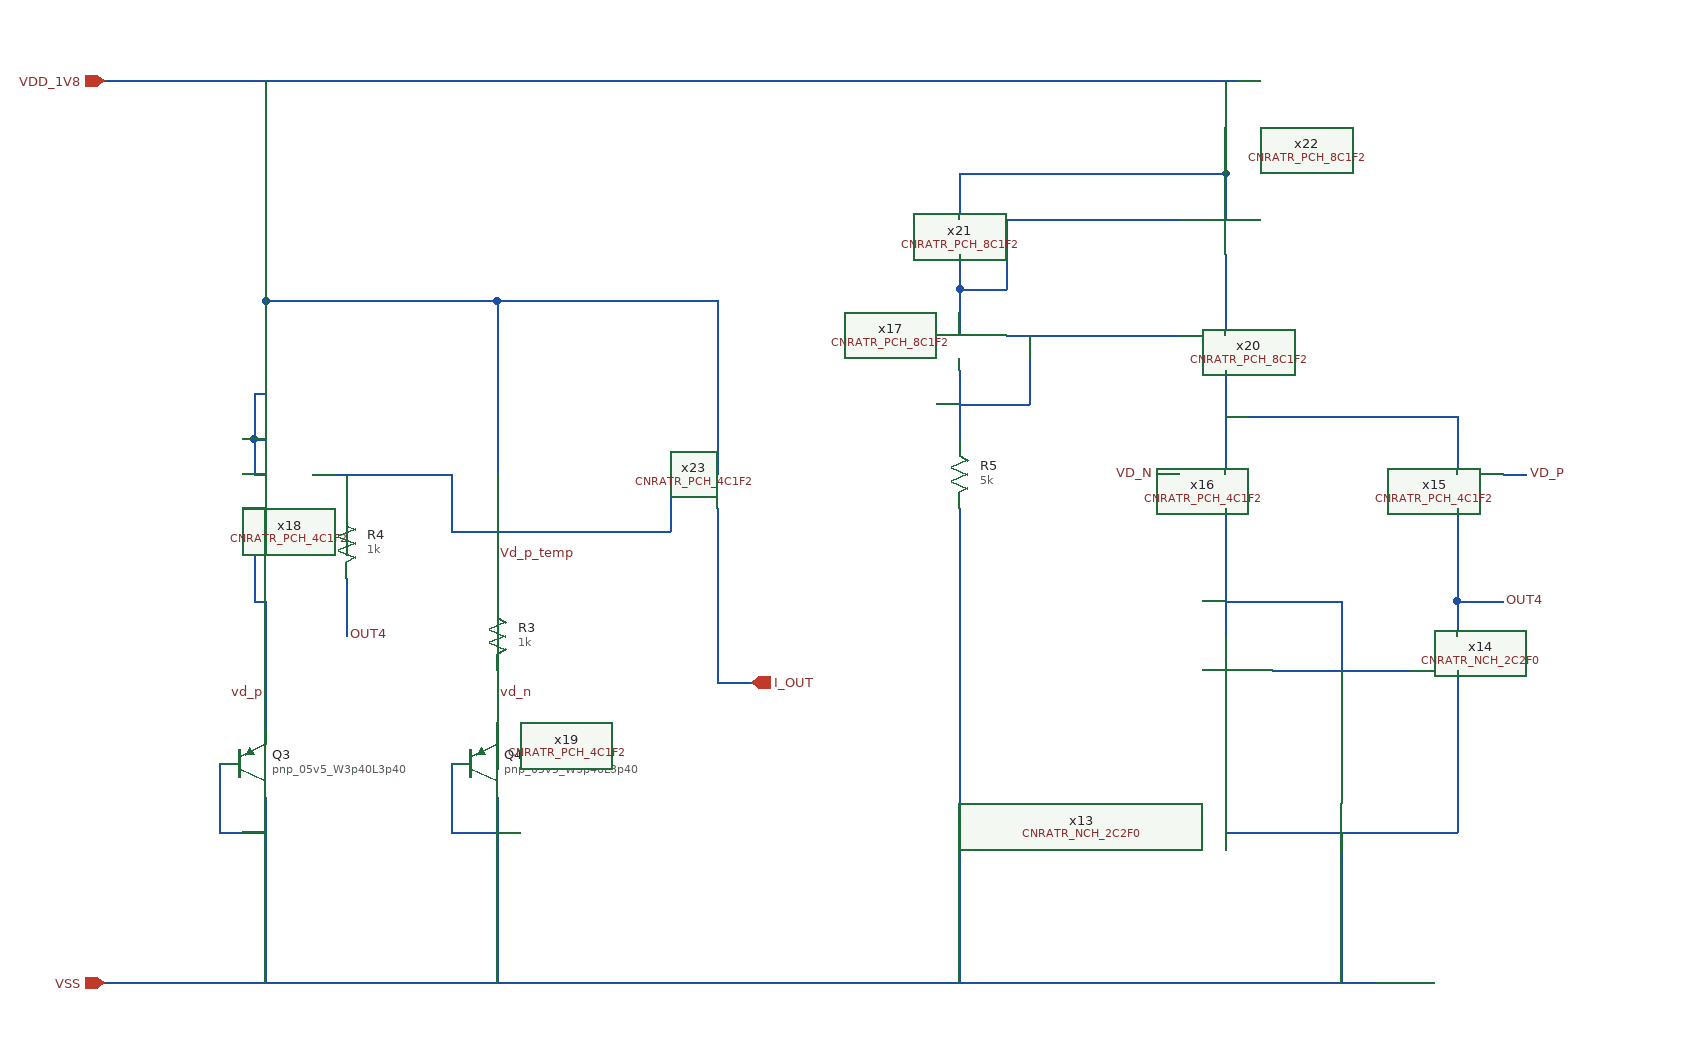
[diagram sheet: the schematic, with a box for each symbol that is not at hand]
v {xschem version=3.4.4 file_version=1.2
}
G {}
K {}
V {}
S {}
E {}
N -40 250 -40 310 {
lab=VSS}
N 160 250 160 310 {
lab=VSS}
N 160 310 180 310 {
lab=VSS}
N 200 280 200 330 {
lab=VSS}
N 180 310 200 310 {
lab=VSS}
N 0 290 0 330 {
lab=VSS}
N -40 310 0 310 {
lab=VSS}
N 0 280 0 290 {
lab=VSS}
N 200 -30 200 0 {
lab=VDD_1V8}
N 200 170 200 220 {
lab=vd_n}
N 200 30 200 110 {
lab=Vd_p_temp}
N 40 0 160 0 {
lab=#net1}
N 70 0 70 30 {
lab=#net1}
N 0 170 0 230 {
lab=vd_p}
N 0 110 0 170 {
lab=vd_p}
N 70 90 70 140 {
lab=OUT4}
N 390 30 390 160 {
lab=I_OUT}
N 390 -30 390 0 {
lab=VDD_1V8}
N 160 0 160 50 {
lab=#net1}
N 160 50 350 50 {
lab=#net1}
N 350 0 350 50 {
lab=#net1}
N 0 -130 0 -100 {
lab=VDD_1V8}
N 0 -150 0 -130 {
lab=VDD_1V8}
N 0 -150 200 -150 {
lab=VDD_1V8}
N 200 -150 200 -130 {
lab=VDD_1V8}
N 200 -130 200 -100 {
lab=VDD_1V8}
N 200 -70 200 -30 {
lab=VDD_1V8}
N 200 -150 390 -150 {
lab=VDD_1V8}
N 390 -150 390 -30 {
lab=VDD_1V8}
N 200 -100 200 -70 {
lab=VDD_1V8}
N 0 -100 0 -70 {
lab=VDD_1V8}
N 1030 110 1030 140 {
lab=OUT4}
N 1030 200 1030 250 {
lab=VSS}
N 1030 170 1030 200 {
lab=VSS}
N 1030 60 1030 110 {
lab=OUT4}
N 1030 250 1030 310 {
lab=VSS}
N 1030 110 1070 110 {
lab=OUT4}
N 830 130 830 140 {
lab=#net2}
N 1030 30 1030 60 {
lab=OUT4}
N 1030 -50 1030 -30 {
lab=#net3}
N 830 30 830 130 {
lab=#net2}
N 830 -50 1030 -50 {
lab=#net3}
N 830 -30 830 0 {
lab=#net3}
N 1030 -30 1030 0 {
lab=#net3}
N 830 170 830 310 {
lab=VSS}
N 830 310 1030 310 {
lab=VSS}
N 930 310 930 350 {
lab=VSS}
N 770 0 790 0 {
lab=VD_N}
N 1070 0 1090 0 {
lab=VD_P}
N 870 170 990 170 {
lab=#net2}
N 830 110 930 110 {
lab=#net2}
N 930 110 930 170 {
lab=#net2}
N 830 -180 830 -160 {
lab=#net4}
N 830 -60 830 -30 {
lab=#net3}
N 640 -120 790 -120 {
lab=#net5}
N 600 -160 600 -150 {
lab=#net6}
N 600 -60 660 -60 {
lab=#net5}
N 660 -120 660 -90 {
lab=#net5}
N 600 -150 600 -120 {
lab=#net6}
N 660 -90 660 -60 {
lab=#net5}
N 830 -190 830 -180 {
lab=#net4}
N 600 -190 600 -160 {
lab=#net6}
N 600 -160 640 -160 {
lab=#net6}
N 640 -220 640 -160 {
lab=#net6}
N 600 -260 600 -250 {
lab=VDD_1V8}
N 600 -260 830 -260 {
lab=VDD_1V8}
N 640 -220 790 -220 {
lab=#net6}
N 600 -250 600 -220 {
lab=VDD_1V8}
N 830 -250 830 -220 {
lab=VDD_1V8}
N 830 -260 830 -250 {
lab=VDD_1V8}
N 830 -280 830 -260 {
lab=VDD_1V8}
N 830 -150 830 -120 {
lab=#net4}
N 830 -160 830 -150 {
lab=#net4}
N 600 -90 600 -30 {
lab=#net5}
N 830 -90 830 -60 {
lab=#net3}
N -140 -340 840 -340 {
lab=VDD_1V8}
N -140 440 960 440 {
lab=VSS}
N -0 330 0 440 {
lab=VSS}
N 200 330 200 440 {
lab=VSS}
N 930 350 930 440 {
lab=VSS}
N 600 40 600 440 {
lab=VSS}
N 600 30 600 40 {
lab=VSS}
N 830 -340 830 -280 {
lab=VDD_1V8}
N 0 -340 0 -150 {
lab=VDD_1V8}
N 390 160 390 180 {
lab=I_OUT}
N 390 180 420 180 {
lab=I_OUT}
N -10 30 -0 30 {
lab=vd_p}
N -10 0 -0 0 {
lab=VDD_1V8}
N -10 -30 -0 -30 {
lab=VDD_1V8}
N -10 -30 -10 0 {
lab=VDD_1V8}
N -10 30 -10 110 {
lab=vd_p}
N -10 110 -0 110 {
lab=vd_p}
N -10 -70 -10 -30 {
lab=VDD_1V8}
N -10 -70 -0 -70 {
lab=VDD_1V8}
C {sky130_fd_pr/pnp_05v5.sym} -20 250 0 0 {name=Q3
model=pnp_05v5_W3p40L3p40
m=3
spiceprefix=X
}
C {sky130_fd_pr/pnp_05v5.sym} 180 250 0 0 {name=Q4
model=pnp_05v5_W3p40L3p40
m=4
spiceprefix=X
}
C {/home/peter/aicex/ip/cnr_atr_sky130nm/design/CNR_ATR_SKY130NM/CNRATR_PCH_4C1F2.sym} 40 0 0 1 {name=x18 }
C {/home/peter/aicex/ip/cnr_atr_sky130nm/design/CNR_ATR_SKY130NM/CNRATR_PCH_4C1F2.sym} 160 0 0 0 {name=x19 }
C {devices/lab_pin.sym} 70 140 0 1 {name=p21 sig_type=std_logic lab=OUT4
}
C {devices/res.sym} 200 140 0 0 {name=R3
value=1k
footprint=1206
device=resistor
m=1}
C {devices/lab_pin.sym} 200 190 0 1 {name=p22 sig_type=std_logic lab=vd_n}
C {devices/lab_pin.sym} 0 190 0 0 {name=p15 sig_type=std_logic lab=vd_p}
C {devices/lab_pin.sym} 200 70 0 1 {name=p18 sig_type=std_logic lab=Vd_p_temp}
C {devices/res.sym} 70 60 0 0 {name=R4
value=1k
footprint=1206
device=resistor
m=1}
C {/home/peter/aicex/ip/cnr_atr_sky130nm/design/CNR_ATR_SKY130NM/CNRATR_PCH_4C1F2.sym} 350 0 0 0 {name=x23 }
C {devices/lab_pin.sym} 1070 110 0 1 {name=p14 sig_type=std_logic lab=OUT4
}
C {/home/peter/aicex/ip/cnr_atr_sky130nm/design/CNR_ATR_SKY130NM/CNRATR_NCH_2C2F0.sym} 870 170 0 1 {name=x13 }
C {/home/peter/aicex/ip/cnr_atr_sky130nm/design/CNR_ATR_SKY130NM/CNRATR_NCH_2C2F0.sym} 990 170 0 0 {name=x14 }
C {/home/peter/aicex/ip/cnr_atr_sky130nm/design/CNR_ATR_SKY130NM/CNRATR_PCH_4C1F2.sym} 1070 0 0 1 {name=x15 }
C {/home/peter/aicex/ip/cnr_atr_sky130nm/design/CNR_ATR_SKY130NM/CNRATR_PCH_4C1F2.sym} 790 0 0 0 {name=x16 }
C {devices/lab_pin.sym} 770 0 0 0 {name=p19 sig_type=std_logic lab=VD_N}
C {devices/lab_pin.sym} 1090 0 0 1 {name=p20 sig_type=std_logic lab=VD_P}
C {/home/peter/aicex/ip/cnr_atr_sky130nm/design/CNR_ATR_SKY130NM/CNRATR_PCH_8C1F2.sym} 640 -120 0 1 {name=x17 }
C {/home/peter/aicex/ip/cnr_atr_sky130nm/design/CNR_ATR_SKY130NM/CNRATR_PCH_8C1F2.sym} 790 -120 0 0 {name=x20 }
C {devices/res.sym} 600 0 0 0 {name=R5
value=5k
footprint=1206
device=resistor
m=1}
C {/home/peter/aicex/ip/cnr_atr_sky130nm/design/CNR_ATR_SKY130NM/CNRATR_PCH_8C1F2.sym} 640 -220 0 1 {name=x21 }
C {/home/peter/aicex/ip/cnr_atr_sky130nm/design/CNR_ATR_SKY130NM/CNRATR_PCH_8C1F2.sym} 790 -220 0 0 {name=x22 }
C {devices/ipin.sym} -140 -340 0 0 {name=p1 lab=VDD_1V8}
C {devices/ipin.sym} -140 440 0 0 {name=p2 lab=VSS}
C {devices/opin.sym} 420 180 0 0 {name=p3 lab=I_OUT}
